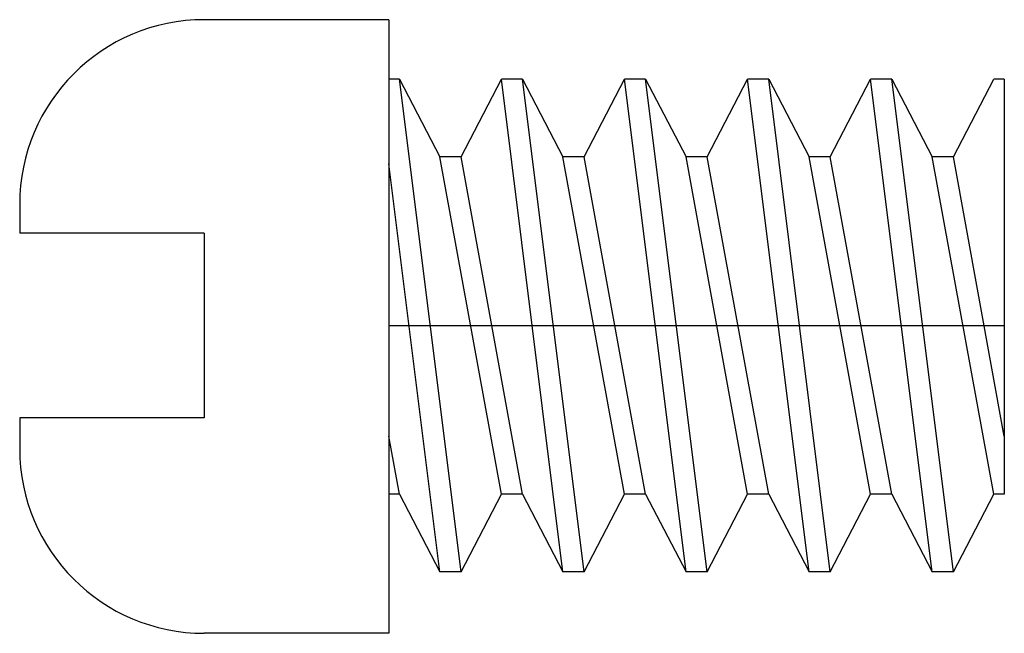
# Model space of a CAD drawing. Units: millimetres. Extents: x 0 to 0.16, y -0.05 to 0.05.
import ezdxf

# ---------------------------------------------------------------- set-up
doc = ezdxf.new("R2010")
doc.units = ezdxf.units.MM

msp = doc.modelspace()

# ---------------------------------------------------------------- linework, layer by layer
for p, q in [((0.06, 0.04968), (0.02924, 0.04968)), ((0.06, 0.04968), (0.06, -0.05)), ((0.06172, 0.04), (0.06, 0.04)), ((0.06172, 0.04), (0.06828, 0.0274)), ((0.07172, -0.04), (0.06172, 0.04)), ((0.07172, 0.0274), (0.07828, 0.04)), ((0.08172, 0.04), (0.07828, 0.04)), ((0.08828, -0.04), (0.07828, 0.04)), ((0.08172, 0.04), (0.08828, 0.0274)), ((0.09172, -0.04), (0.08172, 0.04)), ((0.09172, 0.0274), (0.09828, 0.04)), ((0.10172, 0.04), (0.09828, 0.04)), ((0.10828, -0.04), (0.09828, 0.04)), ((0.10172, 0.04), (0.10828, 0.0274)), ((0.11172, -0.04), (0.10172, 0.04)), ((0.11172, 0.0274), (0.11828, 0.04)), ((0.12172, 0.04), (0.11828, 0.04)), ((0.12828, -0.04), (0.11828, 0.04)), ((0.12172, 0.04), (0.12828, 0.0274)), ((0.13172, -0.04), (0.12172, 0.04)), ((0.13172, 0.0274), (0.13828, 0.04)), ((0.14172, 0.04), (0.13828, 0.04)), ((0.14828, -0.04), (0.13828, 0.04)), ((0.14172, 0.04), (0.14828, 0.0274)), ((0.15172, -0.04), (0.14172, 0.04)), ((0.15172, 0.0274), (0.15828, 0.04)), ((0.16, 0.04), (0.15828, 0.04)), ((0.16, 0.04), (0.16, -0.0274)), ((0.07172, 0.0274), (0.06828, 0.0274)), ((0.07828, -0.0274), (0.06828, 0.0274)), ((0.08172, -0.0274), (0.07172, 0.0274)), ((0.09172, 0.0274), (0.08828, 0.0274)), ((0.09828, -0.0274), (0.08828, 0.0274)), ((0.10172, -0.0274), (0.09172, 0.0274)), ((0.11172, 0.0274), (0.10828, 0.0274)), ((0.11828, -0.0274), (0.10828, 0.0274)), ((0.12172, -0.0274), (0.11172, 0.0274)), ((0.13172, 0.0274), (0.12828, 0.0274)), ((0.13828, -0.0274), (0.12828, 0.0274)), ((0.14172, -0.0274), (0.13172, 0.0274)), ((0.15172, 0.0274), (0.14828, 0.0274)), ((0.15828, -0.0274), (0.14828, 0.0274)), ((0.16, -0.01797), (0.15172, 0.0274)), ((0.16, 0.0274), (0.16, -0.0274)), ((0.06828, -0.04), (0.06, 0.02624)), ((0, 0.01968), (0, 0.015)), ((0.03, 0.015), (0, 0.015)), ((0.03, 0.015), (0.03, -0.015)), ((0.06, 0), (0.16, 0)), ((0.03, -0.015), (0, -0.015)), ((0, -0.015), (0, -0.02)), ((0.06172, -0.0274), (0.06, -0.01797)), ((0.06172, -0.0274), (0.06, -0.0274)), ((0.06172, -0.0274), (0.06828, -0.04)), ((0.07172, -0.04), (0.07828, -0.0274)), ((0.08172, -0.0274), (0.07828, -0.0274)), ((0.08172, -0.0274), (0.08828, -0.04)), ((0.09172, -0.04), (0.09828, -0.0274)), ((0.10172, -0.0274), (0.09828, -0.0274)), ((0.10172, -0.0274), (0.10828, -0.04)), ((0.11172, -0.04), (0.11828, -0.0274)), ((0.12172, -0.0274), (0.11828, -0.0274)), ((0.12172, -0.0274), (0.12828, -0.04)), ((0.13172, -0.04), (0.13828, -0.0274)), ((0.14172, -0.0274), (0.13828, -0.0274)), ((0.14172, -0.0274), (0.14828, -0.04)), ((0.15172, -0.04), (0.15828, -0.0274)), ((0.16, -0.0274), (0.15828, -0.0274)), ((0.07172, -0.04), (0.06828, -0.04)), ((0.09172, -0.04), (0.08828, -0.04)), ((0.11172, -0.04), (0.10828, -0.04)), ((0.13172, -0.04), (0.12828, -0.04)), ((0.15172, -0.04), (0.14828, -0.04)), ((0.06, -0.05), (0.03, -0.05))]:
    msp.add_line(p, q)
for centre, start, end in [((0.03, 0.01968), 90, 180), ((0.03, -0.02), 180, 270)]:
    msp.add_arc(centre, 0.03, start, end)

doc.saveas('drawing.dxf')
